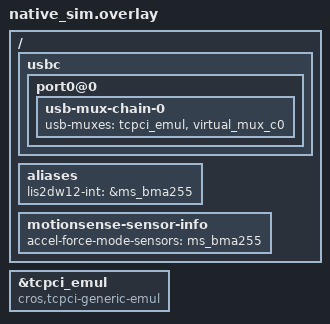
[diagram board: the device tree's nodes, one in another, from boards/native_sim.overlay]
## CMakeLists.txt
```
target_sources(app PRIVATE
    src/battery.c
    src/bb_retimer.c
    src/bma2x2.c
    src/bma4xx.c
    src/bmi_common.c
    src/bmi160.c
    src/bmi260.c
    src/cros_cbi.c
    src/espi.c
    src/gpio.c
    src/integration/usbc/usb.c
    src/integration/usbc/usb_20v_3a_pd_charger.c
    src/integration/usbc/usb_5v_3a_pd_sink.c
    src/integration/usbc/usb_5v_100ma_pd_sink.c
    src/integration/usbc/usb_5v_0a_pd_source.c
    src/integration/usbc/usb_5v_3a_pd_source.c
    src/integration/usbc/usb_attach_src_snk.c
    src/integration/usbc/usb_charging_policy.c
    src/integration/usbc/usb_hard_reset.c
    src/integration/usbc/usb_pd_bist_shared.c
    src/integration/usbc/usb_pd_ctrl_msg.c
    src/integration/usbc/usb_pd_rev3.c
    src/integration/usbc/usb_pd_timer.c
    src/integration/usbc/usb_prl.c
    src/integration/usbc/usb_pe.c
    src/integration/usbc/usb_tc.c
    src/i2c.c
    src/i2c_passthru.c
    src/isl923x.c
    src/led.c
    src/lid_angle.c
    src/lid_switch.c
    src/lis2dw12.c
    src/ln9310.c
    src/locate_chip.c
    src/logging.c
    src/motion_sense/motion_sense.c
    src/port80.c
    src/power_common.c
    src/ppc_sn5s330.c
    src/ppc_syv682x.c
    src/ps8xxx.c
    src/stm_mems_common.c
    src/tablet_mode.c
    src/task.c
    src/tcpci.c
    src/tcpci_test_common.c
    src/tcpm_header.c
    src/tcs3400.c
    src/temp_sensor.c
    src/thermistor.c
    src/touchpad_elan.c
    src/usb_mux.c
    src/util.c
    src/vboot_hash.c
    src/virtual_battery.c
    src/vstore.c
)


# This test does not work when power functions are mocked, so only run it for
# the plain `drivers.default` test case.
zephyr_library_sources_ifndef(CONFIG_POWER_SEQUENCE_MOCK src/chipset.c)
```

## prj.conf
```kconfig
# Copyright 2022 The ChromiumOS Authors
# Use of this source code is governed by a BSD-style license that can be
# found in the LICENSE file.

CONFIG_PLATFORM_EC_CMD_BUTTON=y
CONFIG_PLATFORM_EC_CMD_POWERINDEBUG=y
CONFIG_PLATFORM_EC_CONSOLE_CMD_RTC=y
CONFIG_PLATFORM_EC_CONSOLE_CMD_RTC_ALARM=y
CONFIG_PLATFORM_EC_CONSOLE_CMD_TCPC_DUMP=y
CONFIG_PLATFORM_EC_RTC=y
CONFIG_PLATFORM_EC_VOLUME_BUTTONS=y
# The ztest framework runs on the main thread. Since the main thread is occupied
# by the test runner, the host command subsystem cannot run on the main thread
# and is instead allocated to a dedicated thread
# (CONFIG_EC_HOST_CMD_DEDICATED_THREAD) to avoid blocking the execution of tests
CONFIG_TASK_HOSTCMD_THREAD_MAIN=n
CONFIG_PLATFORM_EC_USBC_PPC_DEDICATED_INT=y

CONFIG_SYSTEM_FAKE=y
CONFIG_GPIO_GET_CONFIG=y
CONFIG_PLATFORM_EC_CHARGER_INPUT_CURRENT_DERATE_PCT=0
CONFIG_PLATFORM_EC_CHARGER_SET_FREQUENCY=y
CONFIG_PLATFORM_EC_LOG_CUSTOM_TIMESTAMP=y
CONFIG_PLATFORM_EC_USB_CHARGER=y
```

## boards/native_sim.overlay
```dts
/* Copyright 2022 The ChromiumOS Authors
 * Use of this source code is governed by a BSD-style license that can be
 * found in the LICENSE file.
 */

#include "../../boards/native_sim.overlay"

/*
 * The TCPCI test verfies the mux behavior in two configurations:
 *   flags = USB_MUX_FLAG_NOT_TCPC;
 *   flags = 0;
 *
 * When USB_MUX_FLAG_NOT_TCPC is set, the TCPCI mux driver must initialize
 * the I2C bus and address from the devicetree.
 *
 * The TCPCI mux doesn't have it's owm emulator and sends it's I2C transactions
 * through the normal TCPCI driver, which then connects to the TCPCI emulator.
 *
 * Use 2 compaible strings here so that the same I2C device node gets setup for
 * both the emulator and the TPCI mux.
 */
&tcpci_emul {
	compatible = "cros,tcpci-generic-emul", "cros-ec,usbc-mux-tcpci";
};

/ {
	usbc {
		port0@0 {
			usb-mux-chain-0 {
				usb-muxes = <&tcpci_emul &virtual_mux_c0>;
			};
		};
	};
};

/ {
	aliases {
		/*
		 * CONFIG_ACCEL_LIS2DW12_INT_EVENT is derived from the aliased
		 * sensor's index, and only motion sensors 0-7 have interrupt
		 * event bits. lis2dw12 is index 8 here, so borrow bma255's
		 * bit 0 (force mode, never raised).
		 */
		lis2dw12-int = &ms_bma255;
	};

	/*
	 * lis2dw12_irq_handler() ignores sensors in forced mode, so keep
	 * the LIS2DW12 interrupt driven for the FIFO tests.
	 */
	motionsense-sensor-info {
		accel-force-mode-sensors = <&ms_bma255>;
	};
};
```

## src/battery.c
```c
/* Copyright 2021 The ChromiumOS Authors
 * Use of this source code is governed by a BSD-style license that can be
 * found in the LICENSE file.
 */

#include "battery.h"
#include "battery_fuel_gauge.h"
#include "crc8.h"
#include "emul/emul_common_i2c.h"
#include "emul/emul_smart_battery.h"
#include "hooks.h"
#include "test/drivers/test_state.h"
#include "test/drivers/utils.h"

#include <zephyr/drivers/emul.h>
#include <zephyr/drivers/gpio.h>
#include <zephyr/drivers/gpio/gpio_emul.h>
#include <zephyr/fff.h>
#include <zephyr/kernel.h>
#include <zephyr/ztest.h>

#define GPIO_BATT_PRES_ODL_PATH NAMED_GPIOS_GPIO_NODE(ec_batt_pres_odl)
#define GPIO_BATT_PRES_ODL_PORT DT_GPIO_PIN(GPIO_BATT_PRES_ODL_PATH, gpios)

FAKE_VALUE_FUNC(int, battery2_write_func, const struct emul *, int, uint8_t,
		int, void *);
FAKE_VALUE_FUNC(int, battery2_read_func, const struct emul *, int, uint8_t *,
		int, void *);

bool authenticate_battery_type(int index, const char *manuf_name);

extern const struct batt_conf_embed *battery_conf;

struct battery_fixture {
	struct i2c_common_emul_data *battery_i2c_common;
	i2c_common_emul_finish_write_func finish_write_func;
	i2c_common_emul_start_read_func start_read_func;
};

static void *battery_setup(void)
{
	static struct battery_fixture fixture;
	static const struct emul *emul = EMUL_DT_GET(DT_NODELABEL(battery));

	fixture.battery_i2c_common =
		emul_smart_battery_get_i2c_common_data(emul);

	return &fixture;
}

static void battery_before(void *data)
{
	struct battery_fixture *fixture = data;

	RESET_FAKE(battery2_write_func);
	RESET_FAKE(battery2_read_func);
	fixture->finish_write_func = fixture->battery_i2c_common->finish_write;
	fixture->start_read_func = fixture->battery_i2c_common->start_read;
}

static void battery_after(void *data)
{
	struct battery_fixture *fixture = data;
	const struct device *dev =
		DEVICE_DT_GET(DT_GPIO_CTLR(GPIO_BATT_PRES_ODL_PATH, gpios));

	/* Reset fake params */
	battery_set_fake_soc(-1);
	battery_set_fake_temp(-1);

	/* Set default state (battery is present) */
	gpio_emul_input_set(dev, GPIO_BATT_PRES_ODL_PORT, 0);

	i2c_common_emul_set_write_func(fixture->battery_i2c_common, NULL, NULL);
	i2c_common_emul_set_read_func(fixture->battery_i2c_common, NULL, NULL);
	fixture->battery_i2c_common->finish_write = fixture->finish_write_func;
	fixture->battery_i2c_common->start_read = fixture->start_read_func;
}

ZTEST_SUITE(battery, drivers_predicate_post_main, battery_setup, battery_before,
	    battery_after, NULL);

ZTEST_USER(battery, test_battery_is_present_gpio)
{
	const struct device *dev =
		DEVICE_DT_GET(DT_GPIO_CTLR(GPIO_BATT_PRES_ODL_PATH, gpios));

	zassert_not_null(dev, NULL);
	/* ec_batt_pres_odl = 0 means battery present. */
	zassert_ok(gpio_emul_input_set(dev, GPIO_BATT_PRES_ODL_PORT, 0));
	zassert_equal(BP_YES, battery_is_present());
	/* ec_batt_pres_odl = 1 means battery missing. */
	zassert_ok(gpio_emul_input_set(dev, GPIO_BATT_PRES_ODL_PORT, 1));
	zassert_equal(BP_NO, battery_is_present());
}

ZTEST(battery, test_authenticate_battery_type)
{
	/* Invalid index */
	zassert_false(authenticate_battery_type(BATTERY_TYPE_COUNT, NULL));
	/* Use fuel-gauge 1's manufacturer name for index 0 */
	zassert_false(
		authenticate_battery_type(0, board_battery_info[1].manuf_name));
	/* Use the correct manufacturer name, but wrong device name (because the
	 * index is 1 and not 0)
	 */
	zassert_false(
		authenticate_battery_type(1, board_battery_info[1].manuf_name));
}

ZTEST(battery, test_board_get_default_battery_type)
{
	zassert_equal(DEFAULT_BATTERY_TYPE, board_get_default_battery_type());
}

ZTEST_F(battery, test_board_cutoff_actuates_driver)
{
	/* We check the return type because board_is_cut_off() is set outside of
	 * board_cut_off_battery() and may be changed by other factors.
	 */

	/* Setup error conditions for battery 1*/
	fixture->battery_i2c_common->finish_write = NULL;
	i2c_common_emul_set_write_func(fixture->battery_i2c_common,
				       battery2_write_func, NULL);

	/* Check that i2c error returns EC_RES_ERROR */
	battery2_write_func_fake.return_val = -1;
	zassert_equal(EC_RES_ERROR, board_cut_off_battery());

	/* Check for OK when i2c succeeds */
	battery2_write_func_fake.return_val = 0;
	zassert_ok(board_cut_off_battery());
}

ZTEST_F(battery, test_sleep)
{
	/* Check 1st battery (lgc,ac17a8m) */
	battery_conf = &board_battery_info[0];
	zassert_equal(EC_ERROR_UNIMPLEMENTED, battery_sleep_fuel_gauge());

	/* Check 2nd battery (panasonic,ap15l5j) */
	battery_conf = &board_battery_info[1];
	fixture->battery_i2c_common->finish_write = NULL;
	i2c_common_emul_set_write_func(fixture->battery_i2c_common,
				       battery2_write_func, NULL);
	zassert_ok(battery_sleep_fuel_gauge());
}

struct battery2_read_data {
	size_t count;
	const uint8_t *values;
};

static int battery2_read(const struct emul *target, int reg, uint8_t *val,
			 int bytes, void *d)
{
	struct battery2_read_data *data = d;

	if (bytes < data->count) {
		*val = data->values[bytes];
	}

	return 0;
}

ZTEST(battery, test_is_charge_fet_disabled__cfet_mask_is_0)
{
	battery_conf = &board_battery_info[2];
	zassert_equal(0, battery_is_charge_fet_disabled());
}

ZTEST_F(battery, test_is_charge_fet_disabled__i2c_error)
{
	/* Set the battery to battery 1 */
	battery_conf = &board_battery_info[1];

	/* Override the finish_write common callback since we don't actually
	 * want to be messing with the emulator.
	 */
	fixture->battery_i2c_common->finish_write = NULL;

	/* Set up an error condition for battery 1 to fail writing to i2c */
	battery2_write_func_fake.return_val = -1;
	i2c_common_emul_set_write_func(fixture->battery_i2c_common,
				       battery2_write_func, NULL);

	/* Verify the error */
	zassert_equal(-1, battery_is_charge_fet_disabled());
}

ZTEST_F(battery, test_is_charge_fet_disabled)
{
	static uint8_t values[] = { 0x20, 0x54, 0xFF };

	static struct battery2_read_data data = {
		/* assume no PEC for count. We'll add it later if we need it */
		.count = ARRAY_SIZE(values) - 1,
		.values = values,
	};

	/* TODO(b/279203401): This code should actually live in an API to tell
	 * the emulator what an expected response is, rather than in the test
	 */
	if (IS_ENABLED(CONFIG_SMBUS_PEC)) {
		uint8_t pec;

		/* make room for the R/W bit */
		const uint8_t addr_8bit = 0xb << 1;

		/* from the DT battery node, grab fet_reg_addr,
		 * default is 0x0 MFG
		 */
		const uint8_t reg =
			DT_PROP_OR(DT_NODELABEL(battery), fet_reg_addr, 0x0);

		/* copied from i2c_controller.c:platform_ec_i2c_read
		 *
		 * We start our CRC with the front part of the i2c packet,
		 * which is the host driving address+reg/cmd, and then
		 * redriving address with read bit. This goes into "out"
		 * Then we complete the CRC across the two data bytes.
		 * This is the target driving it back.
		 * Finally, we'll append PEC to the end of the data, also
		 * something the target would return back.
		 * See: SMBUS Specification 3.2 page 40, & Sec 6.5
		 * http://smbus.org/specs/SMBus_3_2_20220112.pdf
		 */

		const uint8_t out[3] = { addr_8bit, reg, addr_8bit | 1 };

		pec = cros_crc8(out, ARRAY_SIZE(out));
		pec = cros_crc8_arg(values, ARRAY_SIZE(values) - 1, pec);

		values[ARRAY_SIZE(values) - 1] = pec;
		data.count++; /* update for PEC */
	}

	/* Set up the fake read function */
	battery2_read_func_fake.custom_fake = battery2_read;
	i2c_common_emul_set_read_func(fixture->battery_i2c_common,
				      battery2_read_func, &data);

	/* Override the finish_write and start_read common callback since we
	 * don't actually want to be messing with the emulator.
	 */
	fixture->battery_i2c_common->finish_write = NULL;
	fixture->battery_i2c_common->start_read = NULL;

	int rv = battery_is_charge_fet_disabled();

	zassert_equal(1, rv, "RV=%x", rv);
}

ZTEST_F(battery, test_get_disconnect_state__fail_i2c_read)
{
	/* Use battery 0 */
	battery_conf = &board_battery_info[0];

	/* Configure i2c to fail on read */
	battery2_read_func_fake.return_val = -1;
	i2c_common_emul_set_read_func(fixture->battery_i2c_common,
				      battery2_read_func, NULL);

	/* Check for disconnect error */
	zassert_equal(BATTERY_DISCONNECT_ERROR, battery_get_disconnect_state());
}

ZTEST_F(battery, test_get_disconnect_state)
{
	uint8_t values[] = { 0x00, 0x20, 0xFF };
	struct battery2_read_data data = {
		/* assume no PEC for count. We'll add it later if we need it */
		.count = ARRAY_SIZE(values) - 1,
		.values = values,
	};

	/* Use battery 0 */
	battery_conf = &board_battery_info[0];

	/* TODO(b/279203401): This code should actually live in an API to tell
	 * the emulator what an expected response is, rather than in the test
	 */
	if (IS_ENABLED(CONFIG_SMBUS_PEC)) {
		uint8_t pec;

		/* make room for the R/W bit */
		const uint8_t addr_8bit = 0xb << 1;

		/* reg is normally 0x0 for manufacturer access, but it can
		 * come from elsewhere. use the device tree for this purpose
		 */
		uint8_t mfg_reg = DT_PROP_OR(DT_NODELABEL(battery),
					     ship_mode_reg_addr, 0x0);
		const uint8_t out[3] = { addr_8bit, mfg_reg, addr_8bit | 1 };

		pec = cros_crc8(out, ARRAY_SIZE(out));
		pec = cros_crc8_arg(values, 2, pec);

		values[2] = pec;
		data.count = 3; /* update for PEC */
	}

	/* Enable i2c reads and set them to always return 0x2000 */
	battery2_read_func_fake.custom_fake = battery2_read;
	i2c_common_emul_set_read_func(fixture->battery_i2c_common,
				      battery2_read_func, &data);

	int rv = battery_get_disconnect_state();

	zassert_equal(BATTERY_DISCONNECTED, rv, "RV=%x", rv);
}

/* Test setting, getting, and applying fake SoC and temperature parameters */
ZTEST(battery, test_battery_fake_params)
{
	struct batt_params batt = { 0 };

	batt.full_capacity = 5000;
	batt.flags = BATT_FLAG_BAD_TEMPERATURE | BATT_FLAG_BAD_STATE_OF_CHARGE |
		     BATT_FLAG_BAD_REMAINING_CAPACITY;

	battery_set_fake_soc(75);
	battery_set_fake_temp(3000);

	zassert_equal(75, battery_get_fake_soc());
	zassert_equal(3000, battery_get_fake_temp());

	battery_apply_fake_params(&batt);

	zassert_equal(75, batt.state_of_charge);
	zassert_equal(3000, batt.temperature);
	zassert_equal(3750, batt.remaining_capacity);
	zassert_false(batt.flags & BATT_FLAG_BAD_TEMPERATURE);
	zassert_false(batt.flags & BATT_FLAG_BAD_STATE_OF_CHARGE);
	zassert_false(batt.flags & BATT_FLAG_BAD_REMAINING_CAPACITY);
}

static int soc_change_hook_count;
static void soc_change_hook_handler(void)
{
	soc_change_hook_count++;
}
DECLARE_HOOK(HOOK_BATTERY_SOC_CHANGE, soc_change_hook_handler,
	     HOOK_PRIO_DEFAULT);

void check_battery_soc_change(struct batt_params batt);

/* Test check_battery_soc_change notification logic on SoC and display charge
 * changes */
ZTEST(battery, test_check_battery_soc_change)
{
	struct batt_params batt = { 0 };

	soc_change_hook_count = 0;

	batt.state_of_charge = 50;
	batt.display_charge = 500;
	check_battery_soc_change(batt);
	zassert_equal(1, soc_change_hook_count);

	/* Calling again with same SoC and display charge shouldn't notify */
	check_battery_soc_change(batt);
	zassert_equal(1, soc_change_hook_count);

	/* Calling with changed SoC */
	batt.state_of_charge = 60;
	check_battery_soc_change(batt);
	zassert_equal(2, soc_change_hook_count);

	/* Calling with changed display charge */
	batt.display_charge = 650;
	check_battery_soc_change(batt);
	zassert_equal(3, soc_change_hook_count);

	/* Bad state of charge flag should not trigger on SoC change */
	batt.flags |= BATT_FLAG_BAD_STATE_OF_CHARGE;
	batt.state_of_charge = 70;
	check_battery_soc_change(batt);
	zassert_equal(3, soc_change_hook_count);

	/* Bad state of charge flag should still trigger if display charge
	 * changes */
	batt.display_charge = 700;
	check_battery_soc_change(batt);
	zassert_equal(4, soc_change_hook_count);
}
```

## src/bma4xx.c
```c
/* Copyright 2023 The ChromiumOS Authors
 * Use of this source code is governed by a BSD-style license that can be
 * found in the LICENSE file.
 */

#include "accelgyro.h"
#include "common.h"
#include "driver/accel_bma4xx.h"
#include "emul/emul_bma4xx.h"
#include "emul/emul_common_i2c.h"
#include "i2c.h"
#include "motion_sense.h"
#include "motion_sense_fifo.h"
#include "test/drivers/test_state.h"

#include <zephyr/fff.h>
#include <zephyr/kernel.h>
#include <zephyr/logging/log.h>
#include <zephyr/ztest.h>

#define EMUL EMUL_DT_GET(DT_NODELABEL(bma422_emul))
#define SENSOR bma4xx_emul_get_sensor_data(EMUL)

LOG_MODULE_REGISTER(test_bma4xx, LOG_LEVEL_INF);

ZTEST_SUITE(bma4xx, drivers_predicate_post_main, NULL, NULL, NULL, NULL);

static int read_wrong_chip_id(const struct emul *target, int reg, uint8_t *val,
			      int bytes, void *data)
{
	if (reg == BMA4_CHIP_ID_ADDR) {
		*val = 0x13;
		return 0;
	}
	return 1;
}

ZTEST_USER(bma4xx, test_init)
{
	/* Basic initialization works. */
	zassert_ok(bma4_accel_drv.init(SENSOR));

	/* Sensor gets turned off if it was already on. */
	bma4xx_emul_set_accel_enabled(EMUL, true);
	zassert_ok(bma4_accel_drv.init(SENSOR));
	zassert_false(bma4xx_emul_is_accel_enabled(EMUL));

	/* Unexpected chip ID is an error. */
	i2c_common_emul_set_read_func(bma4xx_emul_get_i2c(EMUL),
				      read_wrong_chip_id, NULL);
	zassert_equal(EC_ERROR_HW_INTERNAL, bma4_accel_drv.init(SENSOR));
}

ZTEST_USER(bma4xx, test_set_range)
{
	/* Sets to ±16g successfully. */
	zassert_ok(bma4_accel_drv.set_range(SENSOR, 16, 0));
	zassert_equal(16, bma4xx_emul_get_accel_range(EMUL));

	/* ±3g with roundup flag is ±4. */
	zassert_ok(bma4_accel_drv.set_range(SENSOR, 3, 1));
	zassert_equal(4, bma4xx_emul_get_accel_range(EMUL));

	/* .. ±2g without roundup flag. */
	zassert_ok(bma4_accel_drv.set_range(SENSOR, 3, 0));
	zassert_equal(2, bma4xx_emul_get_accel_range(EMUL));

	/* Communication errors bubble up and don't change the range. */
	i2c_common_emul_set_write_fail_reg(bma4xx_emul_get_i2c(EMUL),
					   BMA4_ACCEL_RANGE_ADDR);
	zassert_not_equal(0, bma4_accel_drv.set_range(SENSOR, 8, 0));
	zassert_equal(2, bma4xx_emul_get_accel_range(EMUL));
}

ZTEST_USER(bma4xx, test_data_rate)
{
	int odr;

	/* Requesting zero ODR disables the sensor. */
	bma4xx_emul_set_accel_enabled(EMUL, true);
	zassert_ok(bma4_accel_drv.set_data_rate(SENSOR, 0, 0));
	zassert_false(bma4xx_emul_is_accel_enabled(EMUL));

	/*
	 * Minimum supported ODR is 0.78125 Hz; smaller requested values should
	 * still yield a nonzero ODR and enable a previously-disabled sensor.
	 */
	zassert_ok(bma4_accel_drv.set_data_rate(SENSOR, 200, 0));
	zassert_true(bma4xx_emul_is_accel_enabled(EMUL));
	odr = bma4_accel_drv.get_data_rate(SENSOR);
	zassert_equal(781, odr, "actual reported data rate was %d mHz", odr);
	zassert_equal(781, bma4xx_emul_get_odr(EMUL),
		      "emulator ODR did not match driver ODR");

	/*
	 * Faster than can be supported goes to the maximum possible ODR. 4 kHz
	 * rounds down to 3.2 kHz which is still too high, so we actually get
	 * 1.6 kHz.
	 */
	zassert_ok(bma4_accel_drv.set_data_rate(SENSOR, 4000 * 1000, 0));
	odr = bma4_accel_drv.get_data_rate(SENSOR);
	zassert_equal(1600 * 1000, odr, "actual reported data rate was %d mHz",
		      odr);
	zassert_equal(1600 * 1000, bma4xx_emul_get_odr(EMUL),
		      "emulator ODR did not match driver ODR");

	/* Rounds up only if requested, otherwise down. */
	zassert_ok(bma4_accel_drv.set_data_rate(SENSOR, 160 * 1000, 0));
	odr = bma4xx_emul_get_odr(EMUL);
	zassert_equal(100 * 1000, odr, "actual ODR was %d", odr);
	zassert_ok(bma4_accel_drv.set_data_rate(SENSOR, 160 * 1000, 1));
	odr = bma4xx_emul_get_odr(EMUL);
	zassert_equal(200 * 1000, odr, "actual ODR was %d", odr);

	/* Communication errors bubble up and reported ODR is unchanged. */
	i2c_common_emul_set_write_fail_reg(bma4xx_emul_get_i2c(EMUL),
					   BMA4_ACCEL_CONFIG_ADDR);
	zassert_not_equal(0,
			  bma4_accel_drv.set_data_rate(SENSOR, 100 * 1000, 0));
	zassert_equal(200 * 1000, bma4_accel_drv.get_data_rate(SENSOR));
}

ZTEST_USER(bma4xx, test_read_data)
{
	intv3_t acceleration;

	bma4xx_emul_set_accel_data(EMUL, 627, 1, -809);
	zassert_ok(bma4_accel_drv.read(SENSOR, acceleration));
	/*
	 * read() returns raw sensor data, which is shifted. The consumer of the
	 * data is expected to know this and possibly also compensate for
	 * scaling when the sensitivity changes.
	 */
	zassert_equal(acceleration[0], 627 << 4, "actual value was %d",
		      acceleration[0]);
	zassert_equal(acceleration[1], 1 << 4, "actual value was %d",
		      acceleration[1]);
	zassert_equal(acceleration[2], -(809 << 4), "actual value was %d",
		      acceleration[2]);

	/* Communication errors bubble up. */
	i2c_common_emul_set_read_fail_reg(bma4xx_emul_get_i2c(EMUL),
					  BMA4_DATA_8_ADDR);
	zassert_not_equal(bma4_accel_drv.read(SENSOR, acceleration), 0);
}

ZTEST_USER(bma4xx, test_offset)
{
	int16_t offsets[] = { 4, -40, 400 };
	int8_t offset_regs[3];
	uint16_t temperature;

	/* set_offset writes offsets successfully. */
	zassert_ok(bma4_accel_drv.set_offset(SENSOR, offsets, 0));
	bma4xx_emul_get_offset(EMUL, &offset_regs);
	/*
	 * Parameter to set_offset is in milli-g, but register values are 3.9mg
	 * per LSb; driver scales the inputs as needed, rounding to nearest
	 * integer.
	 */
	zassert_equal(offset_regs[0], 1, "actual value is %d", offset_regs[0]);
	zassert_equal(offset_regs[1], -10, "actual value is %d",
		      offset_regs[1]);
	zassert_equal(offset_regs[2], 103, "actual value is %d",
		      offset_regs[2]);

	/* get_offset agrees with the programmed offsets, scaled back to mg. */
	memset(offsets, 0, sizeof(offsets));
	zassert_ok(bma4_accel_drv.get_offset(SENSOR, offsets, &temperature));
	zassert_equal(offsets[0], 4, "actual value is %d", offsets[0]);
	zassert_equal(offsets[1], -39, "actual value is %d", offsets[1]);
	zassert_equal(offsets[2], 402, "actual value is %d", offsets[2]);

	/* Out of range offsets are clamped to the accepted range. */
	offsets[0] = 684;
	offsets[1] = -800;
	offsets[2] = 0;
	zassert_ok(bma4_accel_drv.set_offset(SENSOR, offsets, 0));
	bma4xx_emul_get_offset(EMUL, &offset_regs);
	zassert_equal(offset_regs[0], 127);
	zassert_equal(offset_regs[1], -128);
	zassert_equal(offset_regs[2], 0);

	/* Communication errors bubble up. */
	i2c_common_emul_set_write_fail_reg(bma4xx_emul_get_i2c(EMUL),
					   BMA4_OFFSET_1_ADDR);
	zassert_not_equal(bma4_accel_drv.set_offset(SENSOR, offsets, 0), 0);
	i2c_common_emul_set_read_fail_reg(bma4xx_emul_get_i2c(EMUL),
					  BMA4_OFFSET_0_ADDR);
	zassert_not_equal(
		bma4_accel_drv.get_offset(SENSOR, offsets, &temperature), 0);
}

ZTEST_USER(bma4xx, test_resolution)
{
	/* Resolution is always 12 bits. */
	zassert_equal(bma4_accel_drv.get_resolution(SENSOR), 12);
}

ZTEST_USER(bma4xx, test_interrupt)
{
	uint8_t int_map_data, int1_io_ctrl;
	bool int_latched_mode;
	const uint8_t two_frames_data[] = {
		4 << 4,
		0,
		(42 & 0xF) << 4,
		42 >> 4,
		(421 & 0xF) << 4,
		421 >> 4,
		0,
		0,
		0,
		0,
		1 << 4,
		0,
	};
	uint32_t evt = CONFIG_ACCEL_BMA4XX_INT_EVENT;
	struct ec_response_motion_sensor_data host_data[8];
	int host_frames_read;
	uint16_t host_data_sz;

	/* Run init to get interrupts configured. */
	zassert_ok(bma4_accel_drv.init(SENSOR));
	/* Verify interrupt configuration is as expected. */
	zassert_true(bma4xx_emul_is_fifo_enabled(EMUL));
	int_map_data = bma4xx_emul_get_interrupt_config(EMUL, &int1_io_ctrl,
							&int_latched_mode);
	zassert_equal(int_map_data, 0x07); /* all interrupts on INT1 */
	/* INT1 output enabled, active-low push-pull. */
	zassert_equal(int1_io_ctrl, 0x08);
	zassert_true(int_latched_mode);

	/* Ensure every sample gets queued to the AP. */
	SENSOR->oversampling_ratio = 1;

	/* Queue two samples of data and run the interrupt handler. */
	bma4xx_emul_set_fifo_data(EMUL, two_frames_data,
				  sizeof(two_frames_data));
	zassert_ok(bma4_accel_drv.irq_handler(SENSOR, &evt));

	/*
	 * Retrieve the data that should have been queued for the host by the
	 * interrupt handler.
	 */
	host_frames_read = motion_sense_fifo_read(sizeof(host_data),
						  ARRAY_SIZE(host_data),
						  &host_data, &host_data_sz);
	BUILD_ASSERT(ARRAY_SIZE(host_data) > 4,
		     "must be possible to retrieve "
		     "more than the expected number of frames");
	zassert_equal(host_frames_read, 4,
		      "actually put %d frames into the FIFO", host_frames_read);

	/* First frame is a timestamp which we don't care about. */
	zassert_equal(host_data[0].flags, MOTIONSENSE_SENSOR_FLAG_TIMESTAMP);
	/* Next is the first sample from the sensor. */
	zassert_equal(host_data[1].flags, 0);
	zassert_equal(host_data[1].sensor_num, bma4xx_emul_get_sensor_num(EMUL),
		      "data was generated by an unexpected sensor");
	zassert_equal(host_data[1].data[0], 0x40, "X accel was %d",
		      host_data[1].data[0]);
	zassert_equal(host_data[1].data[1], 42 << 4, "Y accel was %d",
		      host_data[1].data[1]);
	zassert_equal(host_data[1].data[2], 421 << 4, "Z accel was %d",
		      host_data[1].data[2]);
	/* Another uninteresting timestamp frame. */
	zassert_equal(host_data[2].flags, MOTIONSENSE_SENSOR_FLAG_TIMESTAMP);
	/* And the second sample from the sensor. */
	zassert_equal(host_data[3].flags, 0);
	zassert_equal(host_data[3].sensor_num, bma4xx_emul_get_sensor_num(EMUL),
		      "data was generated by an unexpected sensor");
	zassert_equal(host_data[3].data[0], 0, "X accel was %d",
		      host_data[3].data[0]);
	zassert_equal(host_data[3].data[1], 0, "Y accel was %d",
		      host_data[3].data[1]);
	zassert_equal(host_data[3].data[2], 1 << 4, "Z accel was %d",
		      host_data[3].data[2]);
}

/** Count read transfers by start register */
struct irq_read_count {
	int int_status_reads;
	int fifo_length_reads;
	int fifo_data_reads;
};

static int count_read_byte(const struct emul *emul, int reg, uint8_t *val,
			   int bytes, void *ctx)
{
	struct irq_read_count *c = ctx;

	if (bytes == 0) {
		if (reg == BMA4_INT_STATUS_1)
			c->int_status_reads++;
		else if (reg == BMA4_FIFO_LENGTH_0_ADDR)
			c->fifo_length_reads++;
		else if (reg == BMA4_FIFO_DATA_ADDR)
			c->fifo_data_reads++;
	}
	/* Fall through to the default emulator handling. */
	return 1;
}

ZTEST_USER(bma4xx, test_irq_burst_reads_first_frame)
{
	const uint8_t one_frame_data[6] = { 4 << 4, 0, 0, 0, 0, 0 };
	uint32_t evt = CONFIG_ACCEL_BMA4XX_INT_EVENT;
	struct irq_read_count count = { 0 };

	zassert_ok(bma4_accel_drv.init(SENSOR));
	SENSOR->oversampling_ratio = 1;

	bma4xx_emul_set_fifo_data(EMUL, one_frame_data, sizeof(one_frame_data));
	i2c_common_emul_set_read_func(bma4xx_emul_get_i2c(EMUL),
				      count_read_byte, &count);
	zassert_ok(bma4_accel_drv.irq_handler(SENSOR, &evt));
	i2c_common_emul_set_read_func(bma4xx_emul_get_i2c(EMUL), NULL, NULL);

	/*
	 * The frame comes with the status burst, then one status re-check
	 * reads 0.
	 */
	zassert_equal(count.int_status_reads, 2);
	zassert_equal(count.fifo_data_reads, 0);
	/* The FIFO length comes from the status burst. */
	zassert_equal(count.fifo_length_reads, 0);
}

/*
 * Report fifo_length = 6 (1 frame) in the status burst so the 2nd frame in
 * the FIFO is left for the status re-check loop rather than drained immediately
 * via BMA4_FIFO_DATA_ADDR.
 */
static int short_burst_read_byte(const struct emul *emul, int reg, uint8_t *val,
				 int bytes, void *ctx)
{
	int cur_reg = reg + bytes;

	count_read_byte(emul, reg, val, bytes, ctx);

	if (cur_reg == BMA4_FIFO_LENGTH_0_ADDR) {
		*val = 6;
		return 0;
	}
	if (cur_reg == BMA4_FIFO_LENGTH_0_ADDR + 1) {
		*val = 0;
		return 0;
	}
	return 1;
}

static const uint8_t two_zero_frames_data[12] = { 4 << 4, 0, 0, 0, 0, 0,
						  4 << 4, 0, 0, 0, 0, 0 };

ZTEST_USER(bma4xx, test_irq_recheck_still_pending)
{
	uint32_t evt = CONFIG_ACCEL_BMA4XX_INT_EVENT;
	struct irq_read_count count = { 0 };

	zassert_ok(bma4_accel_drv.init(SENSOR));
	SENSOR->oversampling_ratio = 1;

	bma4xx_emul_set_fifo_data(EMUL, two_zero_frames_data,
				  sizeof(two_zero_frames_data));
	i2c_common_emul_set_read_func(bma4xx_emul_get_i2c(EMUL),
				      short_burst_read_byte, &count);
	zassert_ok(bma4_accel_drv.irq_handler(SENSOR, &evt));
	i2c_common_emul_set_read_func(bma4xx_emul_get_i2c(EMUL), NULL, NULL);

	/*
	 * Each frame comes with a status burst, then a status re-check reads
	 * 0.
	 */
	zassert_equal(count.int_status_reads, 3);
	zassert_equal(count.fifo_data_reads, 0);
	/* Every FIFO length comes from a status burst. */
	zassert_equal(count.fifo_length_reads, 0);
}

/**
 * This struct captures I2C transactions during the calibration test.
 *
 * Using a bespoke log like this rather than <zephyr/fff.h> fakes is simpler
 * to understand because it records only the relevant information. The
 * calibration_read_byte and calibration_write_byte functions are responsible
 * for logging each read or write transaction into a log, for inspection later.
 */
struct calibration_log {
	struct {
		uint8_t addr;
		bool write;
		uint8_t write_val;
	} activity[256];
	size_t count;
};

static int calibration_read_byte(const struct emul *emul, int reg, uint8_t *val,
				 int bytes, void *ctx)
{
	struct calibration_log *log = ctx;
	/* Sensor is reading 0, 0, +0.992g at 4g sensitivity. */
	const uint8_t acc_data[6] = { 0, 0, 0, 0, (508 & 0xF) << 4, 508 >> 4 };

	zassert_true(log->count <= ARRAY_SIZE(log->activity),
		     "i2c log overflowed");

	reg += bytes; /* burst reads */
	log->activity[log->count].write = false;
	log->activity[log->count].addr = reg;
	log->count++;

	switch (reg) {
	case BMA4_STATUS_ADDR:
		*val = 0x90; /* drdy_acc + cmd_rdy */
		break;
	case BMA4_DATA_8_ADDR:
	case BMA4_DATA_8_ADDR + 1:
	case BMA4_DATA_8_ADDR + 2:
	case BMA4_DATA_8_ADDR + 3:
	case BMA4_DATA_8_ADDR + 4:
	case BMA4_DATA_8_ADDR + 5:
		*val = acc_data[reg - BMA4_DATA_8_ADDR];
		break;
	default:
		*val = 0;
	}
	return 0;
}

static int calibration_write_byte(const struct emul *emul, int reg, uint8_t val,
				  int bytes, void *ctx)
{
	struct calibration_log *log = ctx;

	__ASSERT_NO_MSG(bytes >= 1);
	reg += bytes - 1; /* burst writes */

	log->activity[log->count].write = true;
	log->activity[log->count].addr = reg;
	log->activity[log->count].write_val = val;
	log->count++;

	return 0;
}

ZTEST_USER(bma4xx, test_calibration)
{
	struct calibration_log log = {
		.count = 0,
	};
	size_t log_asserted = 0;

/**
 * Macro that walks through the calibration log, asserting on each operation.
 *
 * Each use of ASSERT_NEXT consumes the oldest entry (increments log_asserted)
 * and checks that entry for being the correct kind of transaction against the
 * expected register, and that the expected value was written if it was a write.
 */
#define ASSERT_NEXT(want_write, want_addr, want_write_val)                     \
	do {                                                                   \
		zassert_true(log_asserted < log.count,                         \
			     "no more logs to check (have %d entries)",        \
			     log.count);                                       \
                                                                               \
		bool was_write = log.activity[log_asserted].write;             \
		zassert_equal(was_write, want_write,                           \
			      "transaction at index %d was a %s",              \
			      log_asserted, was_write ? "write" : "read");     \
                                                                               \
		uint8_t addr = log.activity[log_asserted].addr;                \
		zassert_equal(addr, want_addr,                                 \
			      "transaction at index %d was with register %#x", \
			      log_asserted, addr);                             \
                                                                               \
		if (want_write) {                                              \
			uint8_t write_val =                                    \
				log.activity[log_asserted].write_val;          \
			zassert_equal(write_val, want_write_val,               \
				      "write at index %d wrote value %#x",     \
				      log_asserted, write_val);                \
		}                                                              \
		log_asserted++;                                                \
	} while (0)

#define ASSERT_R(addr) ASSERT_NEXT(false, addr, 0)
#define ASSERT_W(addr, val) ASSERT_NEXT(true, addr, val)
#define ASSERT_RW(addr, val)         \
	do {                         \
		ASSERT_R(addr);      \
		ASSERT_W(addr, val); \
	} while (0)

	/* Range must be set before calibration. */
	zassert_ok(bma4_accel_drv.set_range(SENSOR, 4, 0));

	/* Record transactions in the log. */
	i2c_common_emul_set_read_func(bma4xx_emul_get_i2c(EMUL),
				      calibration_read_byte, &log);
	i2c_common_emul_set_write_func(bma4xx_emul_get_i2c(EMUL),
				       calibration_write_byte, &log);

	zassert_ok(bma4_accel_drv.perform_calib(SENSOR, 1));

	/* Log messages help determine where failures occur when they happen. */
	LOG_INF("Verify configuration readout");
	/* Read current configuration to store back on completion. */
	ASSERT_R(BMA4_ACCEL_CONFIG_ADDR);
	ASSERT_R(BMA4_ACCEL_RANGE_ADDR);
	ASSERT_R(BMA4_FIFO_CONFIG_1_ADDR);
	ASSERT_R(BMA4_POWER_CTRL_ADDR);
	ASSERT_R(BMA4_POWER_CONF_ADDR);
	LOG_INF("Verify configuration setting for calibration");
	/* Disabled offset. */
	ASSERT_RW(BMA4_NV_CONFIG_ADDR, 0);
	/* Disabled FIFO. */
	ASSERT_W(BMA4_FIFO_CONFIG_1_ADDR, 0);
	/* Configured to 50 Hz continuous mode. */
	ASSERT_W(BMA4_ACCEL_CONFIG_ADDR, 0xb7);
	/* Enabled sensor. */
	ASSERT_RW(BMA4_POWER_CTRL_ADDR, 0x04);
	/* Power save mode disabled. */
	ASSERT_RW(BMA4_POWER_CONF_ADDR, 0);

	/* Reads 32 samples, polling for data ready before each read. */
	LOG_INF("Verify calibration data capture");
	for (int i = 0; i < 32; i++) {
		ASSERT_R(BMA4_STATUS_ADDR);
		ASSERT_R(BMA4_DATA_8_ADDR);
		ASSERT_R(BMA4_DATA_8_ADDR + 1);
		ASSERT_R(BMA4_DATA_8_ADDR + 2);
		ASSERT_R(BMA4_DATA_8_ADDR + 3);
		ASSERT_R(BMA4_DATA_8_ADDR + 4);
		ASSERT_R(BMA4_DATA_8_ADDR + 5);
	}

	/*
	 * Wrote new offset. It's a small positive Z axis offset since we're
	 * reading not quite 1g on Z.
	 */
	LOG_INF("Verify expected offset applied");
	ASSERT_W(BMA4_OFFSET_0_ADDR, 0);
	ASSERT_W(BMA4_OFFSET_1_ADDR, 0);
	ASSERT_W(BMA4_OFFSET_2_ADDR, 0x1);

	LOG_INF("Verify applied final configuration");
	/* Re-enabled offset. */
	ASSERT_RW(BMA4_NV_CONFIG_ADDR, BMA4_NV_ACCEL_OFFSET_MSK);
	/* Restored the original configuration. */
	ASSERT_W(BMA4_ACCEL_CONFIG_ADDR, 0);
	ASSERT_W(BMA4_ACCEL_RANGE_ADDR, 0);
	ASSERT_W(BMA4_FIFO_CONFIG_1_ADDR, 0);
	ASSERT_W(BMA4_POWER_CTRL_ADDR, 0);
	ASSERT_W(BMA4_POWER_CONF_ADDR, 0);

	zassert_equal(log_asserted, log.count,
		      "logged %d transactions, but only %d were checked",
		      log.count, log_asserted);
}
```

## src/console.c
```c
/* Copyright 2022 The ChromiumOS Authors
 * Use of this source code is governed by a BSD-style license that can be
 * found in the LICENSE file.
 */

#include "builtin/stdio.h"
#include "console.h"
#include "ec_commands.h"
#include "test/drivers/test_state.h"
#include "uart.h"

#include <zephyr/kernel.h>
#include <zephyr/shell/shell_dummy.h>
#include <zephyr/ztest.h>

ZTEST_USER(console, test_printf_overflow)
{
	char buffer[10];

	zassert_equal(-EC_ERROR_OVERFLOW,
		      crec_snprintf(buffer, 4, "1234567890"), NULL);
	zassert_equal(0, strcmp(buffer, "123"), "got '%s'", buffer);
	zassert_equal(-EC_ERROR_OVERFLOW,
		      crec_snprintf(buffer, 4, "%%%%%%%%%%"), NULL);
	zassert_equal(0, strcmp(buffer, "%%%"), "got '%s'", buffer);
}

/* This test is identical to test_buf_notify_null in
 * test/console_edit.c. Please keep them in sync to verify that
 * uart_console_read_buffer works identically in legacy EC and zephyr.
 */
ZTEST_USER(console, test_buf_notify_null)
{
	char buffer[100];
	uint16_t write_count;
	size_t consumed_count;

	/* Flush the console buffer before we start. */
	zassert_ok(uart_console_read_buffer_init(), NULL);

	/* Write a nul char to the buffer. */
	consumed_count = console_buf_notify_chars("ab\0c", 4);

	/* Check if all bytes were consumed by console buffer */
	zassert_equal(consumed_count, 4, "got %d", consumed_count);

	/* Check if the nul is present in the buffer. */
	zassert_ok(uart_console_read_buffer_init(), NULL);
	zassert_ok(uart_console_read_buffer(CONSOLE_READ_RECENT, buffer,
					    sizeof(buffer), &write_count),
		   NULL);
	zassert_equal(0, strncmp(buffer, "abc", 4), "got '%s'", buffer);
	zassert_equal(write_count, 4, "got %d", write_count);
}

ZTEST_USER(console, test_console_read_buffer_invalid_type)
{
	char buffer[100];
	uint16_t write_count;
	uint8_t invalid_type = CONSOLE_READ_RECENT + 1;

	/* Flush the console buffer before we start. */
	zassert_ok(uart_console_read_buffer_init(), NULL);

	zassert_equal(EC_RES_INVALID_PARAM,
		      uart_console_read_buffer(invalid_type, buffer,
					       sizeof(buffer), &write_count),
		      NULL);
}

ZTEST_USER(console, test_console_read_buffer_size_zero)
{
	char buffer[100];
	uint16_t write_count;

	/* Flush the console buffer before we start. */
	zassert_ok(uart_console_read_buffer_init(), NULL);

	zassert_equal(EC_RES_INVALID_PARAM,
		      uart_console_read_buffer(CONSOLE_READ_RECENT, buffer, 0,
					       &write_count),
		      NULL);
}

ZTEST_USER(console, test_uart_buffer_full)
{
	zassert_false(uart_buffer_full(), NULL);
}

static const char *large_string =
	"This is a very long string, it will cause a buffer flush at "
	"some point while printing to the shell. Long long text. Blah "
	"blah. Long long text. Blah blah. Long long text. Blah blah.";
ZTEST_USER(console, test_shell_fprintf_full)
{
	const struct shell *shell_zephyr = get_ec_shell();
	const char *outbuffer;
	size_t buffer_size;

	zassert_true(strlen(large_string) >=
			     shell_zephyr->fprintf_ctx->buffer_size,
		     "large_string is too short, fix test.");

	shell_backend_dummy_clear_output(shell_zephyr);
	shell_fprintf(shell_zephyr, SHELL_NORMAL, "%s", large_string);

	outbuffer = shell_backend_dummy_get_output(shell_zephyr, &buffer_size);
	zassert_true(strncmp(outbuffer, large_string, strlen(large_string)) ==
			     0,
		     "Invalid console output %s", outbuffer);
}

ZTEST_USER(console, test_cprint_too_big)
{
	zassert_true(strlen(large_string) >= CONFIG_SHELL_PRINTF_BUFF_SIZE,
		     "buffer is too short, fix test.");

	zassert_equal(cprintf(CC_COMMAND, "%s", large_string),
		      -EC_ERROR_OVERFLOW, NULL);
	zassert_equal(cputs(CC_COMMAND, large_string), EC_SUCCESS, NULL);
	zassert_equal(cputs(CC_COMMAND, "01234567890123456789012345678\n"),
		      EC_SUCCESS, NULL);
}

ZTEST_USER(console, test_cmd_chan_invalid_mask)
{
	zassert_equal(EC_ERROR_PARAM1,
		      shell_execute_cmd(get_ec_shell(), "chan foobar"));
}

ZTEST_USER(console, test_cmd_chan_set)
{
	char cmd[100];

	zassert_true(crec_snprintf(cmd, sizeof(cmd), "chan %d",
				   CC_MASK(CC_ACCEL)) > 0);
	zassert_ok(shell_execute_cmd(get_ec_shell(), cmd));

	zassert_false(console_channel_is_disabled(CC_COMMAND));
	zassert_false(console_channel_is_disabled(CC_ACCEL));
	zassert_true(console_channel_is_disabled(CC_CHARGER));
}

ZTEST_USER(console, test_cmd_chan_by_name)
{
	const char name[] = "charger";
	char cmd[100];

	console_channel_enable(name);

	/* Toggle 'charger' off */
	zassert_true(crec_snprintf(cmd, sizeof(cmd), "chan %s", name) > 0,
		     "Failed to compose chan %s command.", name);
	zassert_ok(shell_execute_cmd(get_ec_shell(), cmd),
		   "Failed to execute chan %s command.", name);
	zassert_true(console_channel_is_disabled(CC_CHARGER),
		     "Failed to enable %s channel.", name);

	/* Toggle 'charger' on */
	zassert_true(crec_snprintf(cmd, sizeof(cmd), "chan %s", name) > 0,
		     "Failed to compose chan %s command.", name);
	zassert_ok(shell_execute_cmd(get_ec_shell(), cmd),
		   "Failed to execute chan %s command.", name);
	zassert_false(console_channel_is_disabled(CC_CHARGER),
		      "Failed to disable %s channel.", name);
}

ZTEST_USER(console, test_cmd_chan_show)
{
	const struct shell *shell_zephyr = get_ec_shell();
	const char *outbuffer;
	size_t buffer_size;
	char cmd[100];

	zassert_true(crec_snprintf(cmd, sizeof(cmd), "chan %d",
				   CC_MASK(CC_ACCEL)) > 0);
	zassert_ok(shell_execute_cmd(get_ec_shell(), cmd));
	shell_backend_dummy_clear_output(shell_zephyr);
	zassert_ok(shell_execute_cmd(get_ec_shell(), "chan"));
	outbuffer = shell_backend_dummy_get_output(shell_zephyr, &buffer_size);

	zassert_true(
		strstr(outbuffer,
		       "\r\n # Mask     E Channel\r\n 0 00000001 * command\r\n"
		       " 1 00000002 * accel\r\n 2 00000004   charger\r\n") !=
			NULL,
		"Invalid console output %s", outbuffer);
}

ZTEST_USER(console, test_cmd_chan_save_restore)
{
	char cmd[100];

	zassert_true(crec_snprintf(cmd, sizeof(cmd), "chan %d",
				   CC_MASK(CC_ACCEL)) > 0);
	zassert_ok(shell_execute_cmd(get_ec_shell(), cmd));

	zassert_false(console_channel_is_disabled(CC_COMMAND));
	zassert_false(console_channel_is_disabled(CC_ACCEL));
	zassert_true(console_channel_is_disabled(CC_CHARGER));

	zassert_ok(shell_execute_cmd(get_ec_shell(), "chan save"));
	zassert_true(crec_snprintf(cmd, sizeof(cmd), "chan %d",
				   CC_MASK(CC_ACCEL) | CC_MASK(CC_CHARGER)) >
		     0);
	zassert_ok(shell_execute_cmd(get_ec_shell(), cmd));

	zassert_false(console_channel_is_disabled(CC_COMMAND));
	zassert_false(console_channel_is_disabled(CC_ACCEL));
	zassert_false(console_channel_is_disabled(CC_CHARGER));

	zassert_ok(shell_execute_cmd(get_ec_shell(), "chan restore"));

	zassert_false(console_channel_is_disabled(CC_COMMAND));
	zassert_false(console_channel_is_disabled(CC_ACCEL));
	zassert_true(console_channel_is_disabled(CC_CHARGER));
}

ZTEST_SUITE(console, drivers_predicate_post_main, NULL, NULL, NULL, NULL);

ZTEST_USER(console_pre, test_cmd_chan_save_restore)
{
	/* These are not mentioned in ec-console in native_sim.overlay. */
	zassert_false(console_channel_is_disabled(CC_COMMAND));
	zassert_false(console_channel_is_disabled(CC_ACCEL));
	zassert_false(console_channel_is_disabled(CC_CHARGER));
	/* These are disabled in ec-console in native_sim.overlay. */
	zassert_true(console_channel_is_disabled(CC_EVENTS));
	zassert_true(console_channel_is_disabled(CC_LPC));
	zassert_true(console_channel_is_disabled(CC_HOSTCMD));

	/* Disable an invalid channel, and verify nothing changed. */
	console_channel_disable("not_a_valid_channel");

	zassert_false(console_channel_is_disabled(CC_COMMAND));
	zassert_false(console_channel_is_disabled(CC_ACCEL));
	zassert_false(console_channel_is_disabled(CC_CHARGER));
	zassert_true(console_channel_is_disabled(CC_EVENTS));
	zassert_true(console_channel_is_disabled(CC_LPC));
	zassert_true(console_channel_is_disabled(CC_HOSTCMD));
}

ZTEST_SUITE(console_pre, drivers_predicate_pre_main, NULL, NULL, NULL, NULL);
```
